One B-rep face of a CAD part: STEP entity #1340.
In plain terms, the planar face has unit normal (1, 0, 0).
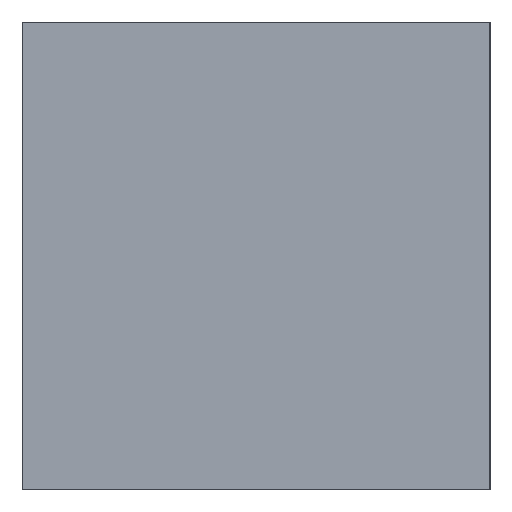
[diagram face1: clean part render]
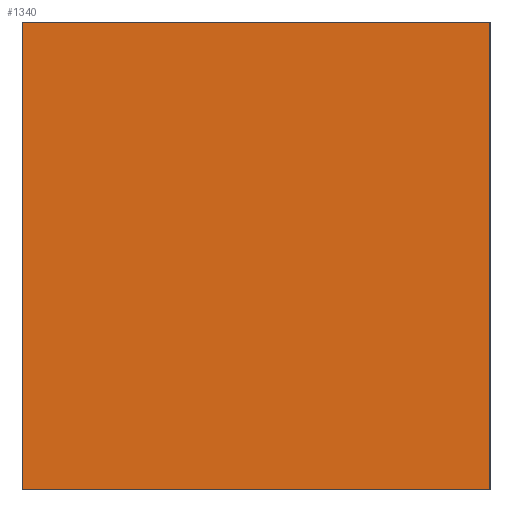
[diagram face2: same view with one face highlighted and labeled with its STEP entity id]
Its self-contained STEP definition (entity closure, numbers rounded to 3 decimals):
#1301=CARTESIAN_POINT('Axis2P3D Location',(-62.5,0.,0.)) ;
#1306=CARTESIAN_POINT('Line Origine',(-62.5,0.,-25.)) ;
#1310=CARTESIAN_POINT('Vertex',(-62.5,-12.5,-25.)) ;
#1312=CARTESIAN_POINT('Vertex',(-62.5,12.5,-25.)) ;
#1315=CARTESIAN_POINT('Line Origine',(-62.5,12.5,-12.5)) ;
#1319=CARTESIAN_POINT('Vertex',(-62.5,12.5,0.)) ;
#1322=CARTESIAN_POINT('Line Origine',(-62.5,0.,0.)) ;
#1326=CARTESIAN_POINT('Vertex',(-62.5,-12.5,0.)) ;
#1329=CARTESIAN_POINT('Line Origine',(-62.5,-12.5,-12.5)) ;
#1302=DIRECTION('Axis2P3D Direction',(1.,0.,0.)) ;
#1303=DIRECTION('Axis2P3D XDirection',(0.,1.,0.)) ;
#1307=DIRECTION('Vector Direction',(0.,1.,0.)) ;
#1316=DIRECTION('Vector Direction',(0.,0.,1.)) ;
#1323=DIRECTION('Vector Direction',(0.,-1.,0.)) ;
#1330=DIRECTION('Vector Direction',(0.,0.,-1.)) ;
#1304=AXIS2_PLACEMENT_3D('Plane Axis2P3D',#1301,#1302,#1303) ;
#1335=ORIENTED_EDGE('',*,*,#1314,.T.) ;
#1336=ORIENTED_EDGE('',*,*,#1321,.T.) ;
#1337=ORIENTED_EDGE('',*,*,#1328,.T.) ;
#1338=ORIENTED_EDGE('',*,*,#1333,.T.) ;
#1308=VECTOR('Line Direction',#1307,1.) ;
#1317=VECTOR('Line Direction',#1316,1.) ;
#1324=VECTOR('Line Direction',#1323,1.) ;
#1331=VECTOR('Line Direction',#1330,1.) ;
#1340=ADVANCED_FACE('MANIFOLD_SOLID_BREP #3622',(#1339),#1305,.T.) ;
#1314=EDGE_CURVE('',#1311,#1313,#1309,.T.) ;
#1321=EDGE_CURVE('',#1313,#1320,#1318,.T.) ;
#1328=EDGE_CURVE('',#1320,#1327,#1325,.T.) ;
#1333=EDGE_CURVE('',#1327,#1311,#1332,.T.) ;
#1334=EDGE_LOOP('',(#1335,#1336,#1337,#1338)) ;
#1339=FACE_OUTER_BOUND('',#1334,.T.) ;
#1309=LINE('Line',#1306,#1308) ;
#1318=LINE('Line',#1315,#1317) ;
#1325=LINE('Line',#1322,#1324) ;
#1332=LINE('Line',#1329,#1331) ;
#1305=PLANE('Plane',#1304) ;
#1311=VERTEX_POINT('',#1310) ;
#1313=VERTEX_POINT('',#1312) ;
#1320=VERTEX_POINT('',#1319) ;
#1327=VERTEX_POINT('',#1326) ;
